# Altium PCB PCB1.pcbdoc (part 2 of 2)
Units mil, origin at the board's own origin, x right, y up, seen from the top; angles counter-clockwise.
Board outline 4437 x 2665.4 mil, 2 copper layers (Top Layer, Bottom Layer), stack 62.206 mil thick; 104 components, 76 nets, 470 pads, 389 vias.

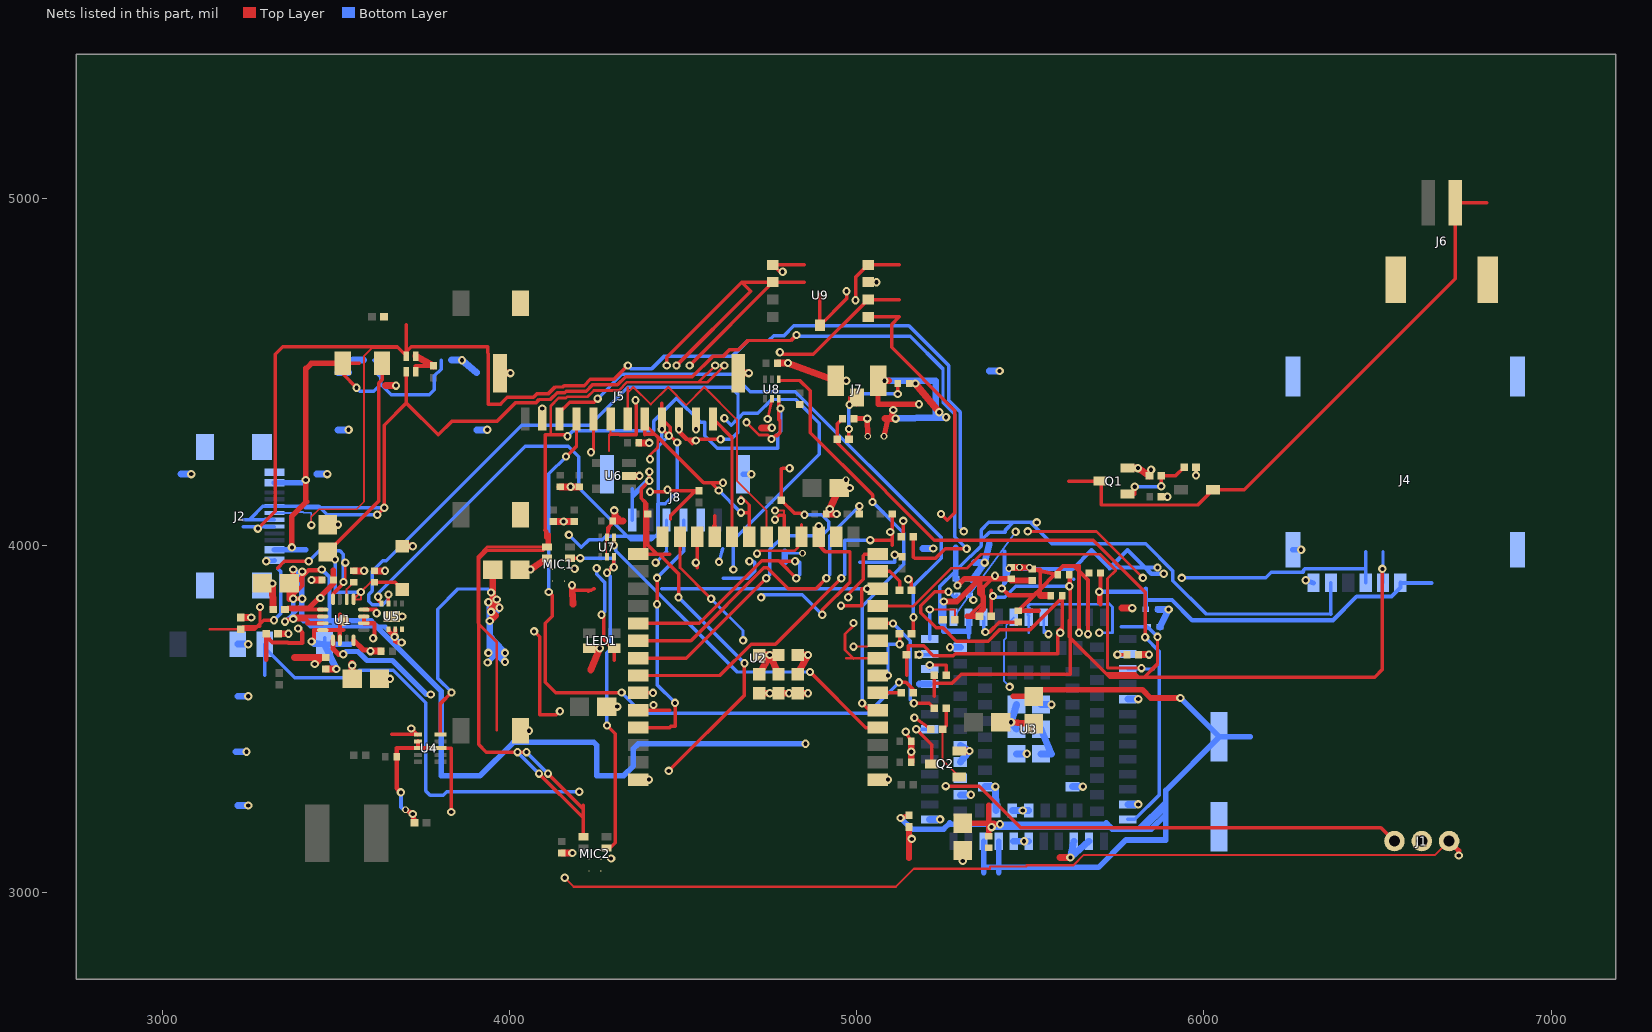
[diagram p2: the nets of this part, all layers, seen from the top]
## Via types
v1: diameter 24, hole 12, Top Layer to Bottom Layer, 378 vias
v2: diameter 19.8, hole 11.8, Top Layer to Bottom Layer, 8 vias
v3: diameter 19.7, hole 11.8, Top Layer to Bottom Layer, 3 vias

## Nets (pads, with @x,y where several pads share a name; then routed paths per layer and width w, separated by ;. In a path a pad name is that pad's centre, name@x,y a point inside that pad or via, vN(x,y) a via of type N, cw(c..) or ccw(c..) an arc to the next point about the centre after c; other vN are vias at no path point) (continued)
GND: C1.2 C2.2 C3.2 C4.2 C5.2 C6.2 C7.2 C8.2 C9.2 C10.2 C11.2 C12.2 C13.2 C14.2 C15.2 C16.2 C17.2 C18.2 C19.2 C20.2 C21.2 C22.2 C23.2 C24.2 C25.2 C26.2 C27.2 C28.2 C29.2 C30.2 C31.2 C32.2 C33.2 C34.2 C35.2 C36.2 C37.2 C38.2 C39.2 D1.2 D2.2 D3.2 D4.2 D5.2 D6.2 D8.2 J1.2 J2.8 J2.9 J2.10 J2.11 J2.A1B12 J2.B1A12 J4.5 J4.8 J4.9 J4.10 J4.11 J5.2 J5.13 J5.14 J6.3 J6.4 J7.1 J7.3 J8.2 J8.7 J8.8 LED1.2 MIC1.2 MIC1.3 MIC2.3 Q1.2 Q2.2 R1.2 R2.2 R4.2 R7.2 R8.2 R20.2 R25.2 R27.2 SW1.2 SW2.2 SW3.2 SW4.2 SW5.2 U1.4 U1.6 U1.8 U1.17 U2.1 U2.40 U2.41 U3.1 U3.10 U3.27 U3.34 U3.36 U3.37 U3.40 U3.41 U3.45 U3.46 U3.47 U3.48 U3.70 U3.71 U3.72 U3.73 U3.88 U3.89 U3.90 U3.91 U3.92 U3.93 U3.94 U3.95 U3.100 U4.2 U4.3 U4.8 U5.4 U5.9 U6.2 U7.2 U7.5 U8.2 U9.4 | length 9704.9
  Top Layer w5: U7.2@4278,3966.6 U7.5@4278,4023.4
  Top Layer w8: U7.5@4279.99,4023.45 4280.22,4024.22 4282,4030.86 4289.01,4057.01 v1(4300.71,4100.67) ; v1(4742.73,4363.89) U8.2@4754.99,4421.56
  Top Layer w10: U4.8@3792.11,3415.5 3831.19,3415.5 v1(3831.19,3231.61) ; v1(4179.06,3884.58) 4179.06,3870.89 4179.67,3870.89 4234.33,3870.89 ; 4226.19,3867.09 4234.33,3870.89 ; 4242.5,3874.7 4234.33,3870.89 ; U7.5@4280,4024 4280.22,4024.22 4282,4026 4282,4030.86 4282,4050 4289.01,4057.01 C29.2@4298,4066 ; C29.2@4296.54,4070 4306.03,4075.5 4315.55,4081 ; 4316,4066 4326.5,4070 ; C12.2@4911.54,4090 v1(4921.82,4104.74) ; v1(5140.5,3462.71) C10.2@5156.54,3435 ; C39.2@5150.54,4466 v1(5168.5,4466) ; v1(5165.49,3503.27) R27.2@5212.96,3470 ; C17.2@5505,3931.54 5528.5,3931.5 5528.5,3926.22 5528.5,3874.5 5528.5,3855 ; R25.2@5842.96,4200 v1(5847.66,4217.39) ; C31.2@5876.54,4140 v1(5894.5,4140)
  Top Layer w12: v1(3428.83,3722.9) 3436,3732 3436,3756 3510,3756 3510,3755.5 ; U1.4@3460.95,3755.47 3510,3755.5 ; U1.6@3510,3726 3510,3755.5 ; U1.6@3510.16,3725.95 3510.2,3755.5 ; 3510.2,3800.9 3510.2,3755.5 ; 3520,3755.5 3510.2,3755.5 ; 3674,3300 v1(3686,3288) ; 3674,3300.5 C18.2@3674.04,3390.5 3674,3415.5 U4.3@3735.02,3415.5 ; D2.2@3728.78,4500 3728.8,4517 R7.2@3780,4517.04 ; U4.2@3735.02,3435.18 U4.3@3735.02,3415.5 ; U4.8@3792.11,3415.5 U4.3@3735.02,3415.5 ; v1@5418,3876 5438,3856 5510,3856 ; C16.2@5445,3936.54 C17.2@5505,3931.54 5528.5,3926.22 C14.2@5570.74,3916.74 ; C37.2@5465,3811.54 5525,3811.5 ; C37.2@5466,3812 5510,3856 ; C14.2@5578.46,3915 C14.2@5570.74,3916.74 ; v1(5640,3748) 5640,3926 ; v1(5666,3744) 5666,3900 5640,3926 ; 3510,3755.5 3510.2,3755.5 ; 5510,3856 5528.5,3874.5 C14.2@5570.74,3916.74 ; C14.2@5570.74,3916.74 5594,3940 5626,3940 ; 5626,3940 5640,3940 5640,3926 ; 5626,3940 5640,3926
  Top Layer w15: U1.8@3550,3726 3578,3698 3588,3698 v1(3598.5,3695) ; v2(3699.3,3237.93) v1(3720.09,3225.93) R20.2@3725.46,3200.5 ; SW1.2@4030.9,3465.35 v1(4054.9,3465.4) ; C12.2@4911.54,4090 4928.74,4119.86 4954.8,4165 v2(4968.5,4188.73) ; C12.2@4912,4090 4918,4096 v1(4921.82,4104.74) ; C38.2@4991.54,4365 v1(5029.5,4365) v2(5031.28,4314.03) ; U9.4@5032.38,4758.03 v1(5056.4,4758) ; J7.3@5061.02,4474.1 5061,4406.1 v1(5178.78,4406.1) ; v2(5078.19,4314.14) 5089,4365 ; 5096.5,4365 v1(5104.53,4389.73) ; v2(5468.36,3936.65) 5469.42,3936.5 C17.2@5505,3931.54 ; v2@5475,3936.5 v2(5497,3936.5)
  Top Layer w20: R2.2@3225,3792.04 v1(3255,3792) ; C1.2@3285.63,3890 v1(3315.6,3890) R4.2@3317.96,3815 ; R1.2@3332.04,3745 v1(3362,3745) ; v1(3428.5,3900) C7.2@3458.46,3900 ; C5.2@3470,3643.46 v1(3500,3643.5) ; C3.2@3475,4059.37 v1(3505,4059.4) ; C6.2@3550,3926.54 v1(3580,3926.5) ; v1(3598.5,3695) C21.2@3628.46,3695 ; C2.2@3610,3926.54 v1(3640,3926.5) ; C4.2@3624.37,3615 v1(3654.4,3615) ; 3642,4460 v1(3672,4460) ; U5.9@3660,3795 v1(3690,3795) ; D8.2@3690,3997.4 v1(3720,3997.4) ; D1.2@3728.78,4545 R7.2@3780,4517.04 ; J5.14@3971.5,4495.95 v1(4001.5,4496) ; C19.2@4029.37,3930 v1(4059.4,3930) MIC1.2@4107.01,3962.89 ; J5.2@4093.5,4364.1 v1(4093.5,4394.1) ; C23.2@4125,4068.46 v1(4155,4068.5) C25.2@4185,4068.46 ; C22.2@4145,4168.46 v1(4175,4168.5) C28.2@4200,4168.46 ; C26.2@4150,3113.46 v1(4180,3113.5) ; v1(4179.06,3884.58) 4179.67,3870.89 4181.5,3830 ; LED1.2@4228.98,3703.34 v1(4259,3703.3) 4233,3640 ; C20.2@4279.37,3535 v1(4309.4,3535) ; C29.2@4296.54,4070 4326.5,4070 ; v1(4300.71,4100.67) C29.2@4306.03,4075.5 ; U6.2@4343.31,4199.99 v1(4373.3,4200) ; U2.40@4370.51,3324.8 v1(4400.5,3324.8) ; C27.2@4371.54,4295 v1(4401.5,4295) ; J5.13@4658.51,4495.94 v1(4688.5,4495.9) ; U2.41@4718.94,3573.62 v1(4748.9,3573.6) ; U2.41@4718.94,3628.74 v1(4748.9,3683.9) ; U2.41@4718.94,3683.86 v1(4748.9,3683.9) ; 4725,4338.5 v1(4755,4338.5) ; C30.2@4771.54,4525 v1(4801.5,4525) J7.1@4938.98,4474.1 v1(4969,4474.1) ; U2.41@4774.06,3573.62 v1(4804.1,3573.6) ; U2.41@4774.06,3628.74 v1(4748.9,3683.9) ; U2.41@4774.06,3683.86 v1(4748.9,3683.9) ; U2.41@4829.18,3573.62 v1(4859.2,3573.6) ; U2.41@4829.18,3628.74 v1(4859.2,3683.9) U2.41@4829.18,3683.86 ; C12.2@4911.54,4090 4912,4090 v1(4941.5,4090) ; v1(4921.82,4104.74) 4928.74,4119.86 C11.2@4949.37,4165 4954.8,4165 v1(4979.4,4165) ; U2.1@5059.49,3324.8 v1(5089.5,3324.8) ; J7.3@5061.02,4474.1 5091,4474.1 ; 5081.5,4365 5089,4365 5096.5,4365 v1(5111.5,4365) ; C9.2@5156.54,3375 v1(5156.5,3405) C10.2@5156.54,3435 ; v1(5168.5,4466) v1(5237.42,4383.44) ; Q2.2@5294.37,3407.4 v1(5324.4,3407.4) ; v1(5305,3090.6) C33.2@5305,3120.63 ; C8.2@5414.37,3490 v1(5444.4,3490) C34.2@5510,3485.63 ; C16.2@5445,3936.54 5469.42,3936.5 v2@5475,3936.5 ; 5528.5,3855 C15.2@5558.46,3855 ; 5585,3100.3 v1(5615,3100.3) ; 5763.1,3818.8 v1(5793.1,3818.8) ; Q1.2@5779.37,4222.4 v1(5809.4,4222.4) R25.2@5842.96,4200 ; C36.2@5811.54,3685 v1(5841.5,3685)
  Inner2 w12: v1(5640,3748) 5666,3722 5688,3722 ; v1(5666,3744) 5688,3722 ; v1(5866,3936) 5866,3880 ; v1(5884,3918) 5884,3898 5866,3880 ; 5688,3722 5708,3722 ; 5688,3722 5698,3712 5708,3722 ; 5708,3722 5866,3880
  Bottom Layer w5: U3.95@5278.46,3792.84 5324.22,3855.73 v1(5457.19,4038.74)
  Bottom Layer w6: 4792,3977.11 v2(4842.86,3977.11)
  Bottom Layer w10: SW4.2@3466.02,3715 SW4.2@3466,3733 ; v1(4602.55,3952.06) 4612.9,3990.7 ; 5227.1,4368.7 v1(5237.42,4383.44) ; D5.2@5324,3856 5324.22,3855.73 v1(5335.57,3842.21) ; v1(5417.39,3875.39) 5425,3891.7
  Bottom Layer w12: v1(3686,3288) 3686,3246 3692,3240 v2(3699.3,3237.93) ; 5425,3891.7 5425,3981.7 ; v2@5430,3932 5438.09,3932 5622,3932 5676,3986 5726,3936 ; v1(5866,3936) 5830,3936 ; v1(5884,3918) 5848,3918 5830,3936 ; 5726,3936 5730,3936 ; 5726,3936 5728,3934 5730,3936 ; 5730,3936 5780,3986 5830,3936 ; 5730,3936 5830,3936
  Bottom Layer w15: v1(3297.93,3953.99) J2.A1B12@3321.79,3956.49 ; SW4.2@3466,3714 3436,3714 v1(3428.83,3722.9) SW4.2@3466.02,3715 3541,3715 ; J8.8@4671.79,4204.64 v1(4695.8,4204.6) ; 5425,3891.7 5438.09,3932 v2(5438.29,3932.59) ; J4.8@6255.9,3987.12 v1(6279.9,3987.1) ; v1(6292.98,3899.12) J4.5@6315.8,3891.7
  Bottom Layer w20: 3051.9,4205 v1(3081.9,4205) ; 3211,3405 v1(3241,3405) ; 3216,3250 v1(3246,3250) ; 3216,3565 v1(3246,3565) ; SW5.2@3216.02,3715 v1(3246,3715) ; 3443.6,4205 v1(3473.6,4205) ; SW4.2@3466.02,3715 v1(3500,3643.5) ; 3505.4,4332.7 v1(3535.4,4332.7) ; 3505.4,4497.3 3535.4,4497.3 ; 3548,4533.3 3578,4533.3 ; 3832,4533.3 v1(3862,4533.3) 3904.6,4497.3 ; 3904.6,4332.7 v1(3934.6,4332.7) ; 4792,3951.3 4792,3977.11 4792,3981.3 ; v1(5079,4474.1) 5227.1,4474.1 5227.1,4368.7 ; v1(5111.5,4365) 5227.1,4368.7 ; 5179.6,3599.9 U3.10@5209.57,3599.91 ; 5189.7,3990.7 v1(5219.7,3990.7) ; U3.1@5209.57,3210.16 v1(5239.6,3210.2) ; v1(5257.1,4368.7) 5227.1,4368.7 ; v1(5268.2,3706.2) U3.100@5298.15,3706.22 ; U3.45@5298.15,3281.01 v1(5328.2,3281) ; U3.47@5298.15,3375.51 v1(5324.4,3407.4) U3.48@5298.15,3422.76 ; 5333,3900 v1(5368,3950) ; 5338,3950 v1(5368,3950) ; U3.73@5369.02,3304.64 v1(5399,3304.6) U3.72@5400.51,3235.74 ; 5381.2,4003.1 v1(5368,3950) ; 5381.2,4502.3 v1(5411.2,4502.3) ; U3.71@5447.76,3235.74 v1(5477.8,3235.7) U3.70@5495,3235.74 ; U3.41@5451.69,3147.16 v1(5481.7,3147.2) U3.40@5495,3147.16 ; U3.89@5459.57,3399.12 v1(5489.6,3399.1) ; U3.90@5459.57,3469.99 v1(5444.4,3490) U3.91@5459.57,3540.86 ; U3.94@5530.43,3399.12 5560.4,3399.1 U3.93@5530.43,3469.99 ; U3.92@5530.43,3540.86 v1(5560.4,3540.9) ; U3.88@5620.98,3304.64 v1(5651,3304.6) ; U3.37@5624.92,3147.16 v1(5615,3100.3) U3.36@5668.23,3147.16 ; U3.34@5780.43,3253.45 v1(5810.4,3253.5) ; U3.27@5780.43,3556.61 v1(5810.4,3556.6) ; D3.2@5868,3815 v1(5898,3815) D4.2@5873,3765
  other v1: 4291.7,3097.5 4186.7,3932.5
GPIO0_BOOT: J8.6 R6.1 SW4.1 U2.27 | length 3268.4
  Top Layer w10: U2.27@4370.51,3974.8 4423.2,3974.8 ; U2.27@4388,3978 4388,4126 ; R6.1@4394,4094 4394,4120 4388,4126 ; 4397,4000 R6.1@4397.04,4090 ; 4398,4000 4423.2,3974.8 ; v1(4402,4212) v1(4402,4186) 4378,4162 4378,4136 4388,4126 ; 4424,3974 4423.2,3974.8 ; 4430,3974 4486,3918 v1(4486,3850) ; v1(4458,3350) 4676,3568 v1(4676,3660) ; 4460.5,3974.8 4423.2,3974.8
  Top Layer w15: U2.27@4370.51,3974.8 U2.27@4388,3978
  Inner2 w10: v1(4200,3290) 4260,3350 v1(4458,3350)
  Bottom Layer w10: 3294,3625 SW4.1@3293.98,3715 ; SW4.1@3298,3700 3380,3618 3544,3618 3566,3640 3664,3640 3758,3546 3758,3292 3770,3280 3808,3280 3818,3290 v1(4200,3290) ; J8.6@4352,4072 4352,4136 ; 4352,4162.8 4352,4144 ; J8.6@4352.9,4072 J8.6@4352.89,4072.75 4352.9,4136.9 ; v1(4402,4186) 4352.9,4136.9 ; v1(4402,4212) 4402,4194 4352,4144 ; v1(4486,3850) v1(4676,3660) ; 4352,4136 4352.9,4136.9 ; 4352,4136 4352,4144
I2C_SCL: J5.10 U2.17 U5.7 | length 3579
  Top Layer w9.92: U5.7@3650.16,3831.91 v1(3650.16,3858.19) ; J5.10@4487.24,4364.05 4487.24,4325.63 4507.24,4305.63 4512.37,4305.63 v1(4607.24,4305.63)
  Top Layer w10: v1@4487.2,4329.1 J5.10@4487.2,4364.1 ; v1@4488,4330 4512.37,4305.63 4526,4292 v1(4536,4302) ; U2.17@4888,4022 4888,4002 4908,3982 4980,3982 4980,3894 4900,3814 v1(4900,3800) ; U2.17@4890,4025.2 v1@4890,4060.2
  Inner1 w10: v1(4536,4302) 4554,4302 v1(4618,4366)
  Inner2 w10: v1(4644,3930) v1(4724,3850)
  Bottom Layer w9.92: v1(3650.16,3858.19) 3650.16,3844.47 3633.88,3828.19 3603.88,3828.19 3593.88,3838.19 3593.88,3858.19 3603.88,3868.19 3603.88,3925.63 3633.88,3955.63 3643.88,3955.63 4033.88,4345.63 4229.76,4345.63 4339.76,4455.63 4637.24,4455.63 4657.24,4435.63 4657.24,4365.24 4657.24,4325.63 4637.24,4305.63 v1(4607.24,4305.63)
  Bottom Layer w10: v1(4618,4366) 4638,4346 4657.24,4365.24 4672,4380 4714,4380 4754,4420 4824,4420 4892,4352 4892,4262 4644,4014 v1(4644,3930) ; v1(4724,3850) 4732,3858 4842,3858 v1(4900,3800)
  other v1: 4890,4055.2 4487.2,4334.1
I2C_SDA: J5.9 U2.12 U5.8 | length 3950.8
  Top Layer w9.92: v1(3620.47,3851.91) 3620.47,3841.91 U5.8@3630.47,3831.91 ; J5.9@4438.03,4335.63 v1(4458.03,4315.63)
  Top Layer w10: v1(4438,4334.1) J5.9@4438.03,4364.05 ; 4438,4409.1 J5.9@4438.03,4364.05 ; v1(4482,4296) 4462,4316 4462,4340 J5.9@4438.03,4364.05 ; v1(4954,3826) 5014,3826 5014,3870 ; 5014.5,3874.8 v1(5029.5,3874.8) U2.12@5059.49,3874.8
  Inner2 w10: v1(4170,4030) 4194,4054 4214,4054 4234,4034 4234,4016 4280,4016 4290,4026 4316,4026 4350,3992 4620,3992 4668,3944 4668,3942 4718,3892 4718,3890 4782,3826 v1(4954,3826)
  Bottom Layer w9.92: v1(3620.47,3851.91) 3620.47,3861.91 4044.19,4285.63 4168.03,4285.63 4198.03,4255.63 4198.03,4165.63 4337.66,4026 4348.03,4015.63 4408.03,4015.63 4418.4,4026 4426,4033.6 4428.03,4035.63 4428.03,4120 4428.03,4285.63 4438,4295.6 v1(4458.03,4315.63)
  Bottom Layer w10: v1(4170,4030) 4206,3994 4228,4016 4266,4016 4276,4026 4337.66,4026 4418.4,4026 4426,4026 4426,4033.6 4426,4120 4428.03,4120 4448,4120 4482,4154 v1(4482,4296) ; 4438,3874.8 v1(5029.5,3874.8) ; 4438,4295.6 v1(4438,4334.1)
LCD_BL_PWM: J5.8 U2.21 | length 1098.7
  Top Layer w8: J5.8@4392,4346 4418,4320 ; v1(4404,4248) 4404,4260 4426,4282 4426,4312 ; 4666,4140 4690,4116
  Top Layer w10: 4388,4320 4388.8,4320 ; 4388.8,4319.1 4388.8,4320 ; J5.8@4388.8,4364.1 4388.8,4320 ; v1(4602,4158) 4580,4180 ; v1(4614,4180) 4580,4180 ; v1(4666,4094) 4686,4094 ; v1(4666,4128) v1@4670,4132 ; U2.21@4690,4025.2 4690,4115.2 ; 4388.8,4320 4418,4320 4426,4312 4558,4180 4580,4180
  Inner2 w8: v1(4404,4248) 4414,4258 4548,4258 4666,4140
  Inner2 w10: v1(4614,4180) v1(4666,4128)
  Bottom Layer w10: v1(4602,4158) v1(4666,4094)
LCD_CS: J5.5 U2.18 | length 993.8
  Top Layer w8: v1(4234,4268) 4240,4274 v1@4242,4274 ; v1@4241.2,4274.1 J5.5@4241.2,4364.1 ; v1(4712,3976) 4720,3984 4820,3984 4842,4006 U2.18@4842,4022 ; U2.18@4840,4025.2 4840,4060.2
  Inner2 w8: v1(4234,4268) 4244,4258 4244,4118 4336,4026 4370,4026 4372,4024 4380,4032 4412,4032 4420,4040 4420,4044 4644,4044 v1(4712,3976)
LCD_DC: J5.6 U2.19 | length 1768.3
  Top Layer w6: 4286,4272 4286,4316 4288,4318 ; 4290.4,4319.1 4290.4,4320 J5.6@4290.4,4364.1 ; v1(4764,4100) 4790,4100 ; 4790,4086 4790,4100 ; 4790,4100.2 4790,4100
  Top Layer w10: 4288,4318 4290,4320 4290.4,4320 4314,4320 4316,4318 4364,4318 4364,4416 v1(4362,4418) ; v1(4764,4074) 4776,4086 4790,4086 ; U2.19@4790,4025.2 4790,4085.2
  Inner2 w6: 4286,4272 4566,4272 4592,4272 v1(4764,4100)
  Inner2 w10: v1(4362,4418) 4362,4474 4432,4544 4526,4544 4562,4508 4562,4276 4566,4272 v1(4764,4074)
LCD_MOSI: J5.4 R22.2 | length 1956.3
  Top Layer w10: v1(4111.96,3865.59) 4121.96,3855.59 4121.96,3795.59 4101.96,3775.59 4101.96,3605.59 4131.96,3575.59 v1(4321.96,3575.59) ; v1(4161.96,4255.59) 4191.96,4285.59 J5.4@4191.96,4364.05 ; v1(5121.37,3605) 5141.37,3605 5162.04,3584.33 R22.2@5162.04,3575
  Bottom Layer w10: v1(4111.96,3865.59) 4111.96,4205.59 v1(4161.96,4255.59) ; v1(4321.96,3575.59) 4381.96,3515.59 5031.96,3515.59 v1(5121.37,3605)
LCD_MOSI_MCU: R22.1 U2.6 | length 68.6
  Top Layer w10: U2.6@5059.49,3574.8 5059.7,3575 R22.1@5127.96,3575
LCD_RST: J5.7 U2.20 | length 903.9
  Top Layer w6: J5.7@4339.6,4364.1 4339.6,4454.1 ; 4342,4442 4356,4456 4406,4406 4456,4456 4508,4404 4560,4456 4654,4362 4654,4186 4740,4100 ; U2.20@4740,4025.2 4740,4100 ; 4740,4100.2 4740,4100
LCD_SCLK: J5.3 R23.2 | length 1671.7
  Top Layer w10: J5.3@4142.75,4364.05 4142.75,4382.52 4172.75,4412.52 4242.75,4412.52 v1(4252.75,4422.52) ; R23.2@5157.04,3745 5162.75,3750.71 v1(5162.75,3792.52)
  Bottom Layer w10: v1(4252.75,4422.52) 4322.75,4492.52 4642.75,4492.52 4692.75,4442.52 4822.75,4442.52 5242.75,4022.52 5242.75,3962.52 5162.75,3882.52 v1(5162.75,3792.52)
LCD_SCLK_MCU: R23.1 U2.7 | length 183.7
  Top Layer w10: U2.7@5059.49,3624.8 v1(5089.5,3624.8) ; v1(5123,3715) R23.1@5122.96,3745
  Bottom Layer w10: v1(5089.5,3624.8) 5089.5,3715 v1(5123,3715)
LED_DATA: LED1.3 U2.24 | length 703.7
  Top Layer w10: v1(4264,3800) 4270,3794 4270,3728 4294,3704 LED1.3@4302,3704 ; 4301,3668.3 LED1.3@4301.02,3703.34 ; 4540,3935.2 U2.24@4540,4025.2
  Inner2 w10: v1(4250,3934) 4292,3976 4510,3976 v1(4536,3950)
  Bottom Layer w10: v1(4250,3934) 4250,3916 4274,3892 4274,3810 v1(4264,3800)
LTE_ANT: C38.1 R29.1 U3.35 | length 1862.4
  Top Layer w10: R29.1@4942.96,4305 4942.96,4295 5222.96,4015 5680.43,4015 5830.43,3865 v1(5830.43,3735) ; R29.1@4942.96,4305 4943,4349.5 C38.1@4958.46,4365
  Bottom Layer w10: U3.35@5780.43,3210.16 5800.43,3210.15 5870.43,3280.15 5870.43,3695 v1(5830.43,3735)
LTE_ANT_CONN: C39.1 J7.2 R29.2 | length 346.8
  Top Layer w10: R29.2@4977.04,4305 v1(4977,4335) ; v1(4978.79,4404.69) 4978.79,4425.9 J7.2@5000,4425.9 J7.2@5000,4404.69 ; v1(5117.5,4436) C39.1@5117.46,4466
  Bottom Layer w10: v1(4977,4335) 4977,4404.69 v1(4978.79,4404.69) 5010.09,4436 v1(5117.5,4436)
MIC_CLK_1V8: MIC1.4 MIC2.4 U7.3 | length 1064.8
  Top Layer w6: v1(4299.7,3936.6) U7.3@4299.69,3966.55
  Top Layer w9.92: MIC2.4@4277.99,3127.89 4288.64,3127.89 4303.32,3142.57 4303.32,3457.24 v1(4279.69,3480.87) ; v1(4279.69,3920.87) 4299.69,3940.87 U7.3@4299.69,3966.55
  Top Layer w10: MIC1.4@4172.99,3962.89 v1(4203,3962.9)
  Bottom Layer w9.92: v1(4279.69,3480.87) 4279.69,3690.87 4289.69,3700.87 4289.69,3910.87 v1(4279.69,3920.87)
  Bottom Layer w10: v1(4203,3962.9) 4299.7,3962.9 v1(4299.7,3936.6)
MIC_DATA_1V8: MIC1.1 MIC2.1 U8.3 | length 4968.9
  Top Layer w8: 3962,3468 3962,3722 3910,3774 3908,3776 3908,3968 3936,3996 4106,3996 4107,3996 4114,3996 4114,4032 4112,4032 4107,4037 4105,4039 ; 4102,4044 4102,4042 4102,4022 4106,4018 ; 4118,4318 4118,4402 4140,4424 4162,4424 4166,4428 4224,4428 4242,4446 4314,4446 4338,4470 4544,4470 ; v1(4592,4518) 4544,4470 ; v1(4618,4518) 4570,4470 4544,4470 ; v1(4682,4354) 4718,4318 4744,4318 4748,4314 v1@4762,4314 ; v1(4754,4306) v1@4762,4314 ; 4778,4360 4778,4326 ; v1@4762,4314 4766,4318 4770,4318 4778,4326 ; v1@4762,4314 4770,4314 4778,4322 4778,4326
  Top Layer w10: v1(4048,3404) 3932,3404 3910,3426 3910,3774 3910,3962 3934,3986 4096,3986 MIC1.1@4106,3996 ; v1(4084,3342) 4208,3218 ; 4101,4043 4102,4042 4105,4039 ; 4102,4044 4102,4318 4118,4318 4162,4318 v1(4166,4314) ; MIC1.1@4107.01,3995.26 4107,3996 4107,4037 4107,4040.3 ; v1(4110,3342) 4212,3240 ; MIC2.1@4212.01,3160.26 4212,3240 ; 4212,3250.3 4212,3240 ; 4774.7,4361.6 U8.3@4774.69,4421.56 ; v1@4778,4394 v1(4780,4394)
  Inner2 w8: v1(4592,4518) 4682,4428 v1(4682,4354) ; v1(4618,4518) 4704,4432 4704,4356 v1(4754,4306)
  Bottom Layer w10: v1(4022,3404) v1(4084,3342) ; v1(4048,3404) v1(4110,3342) ; v1(4166,4314) 4182,4330 4414,4330 4414,4358 4480,4424 4550,4354 4562,4354 4562,4316 4598,4280 4772,4280 4772,4320 4780,4328 v1(4780,4394)
MIC_PDM_CLK: U2.4 U7.4 | length 1006.6
  Top Layer w9.92: v1(4299.69,4000.12) U7.4@4299.69,4023.45 ; v1(4865,3634.8) 5025,3474.8 U2.4@5059.49,3474.8
  Bottom Layer w9.92: v1(4299.69,4000.12) 4305.01,3994.8 4305.01,3984.8 4655,3634.8 v1(4865,3634.8)
MIC_PDM_DATA: U2.5 U8.4 | length 1218.6
  Top Layer w9.92: U8.4@4774.69,4478.44 4778.33,4474.8 4835,4474.8 4865,4444.8 4865,4324.8 5045,4144.8 v1(5045,4124.8) ; v1(5015,3544.8) 5035,3524.8 U2.5@5059.49,3524.8
  Bottom Layer w9.92: v1(5015,3544.8) 5015,3824.8 5135,3944.8 5135,4034.8 v1(5045,4124.8)
MICROSD_N5: R12.1 U9.7 | length 3545.6
  Top Layer w10: v1(4404,4154) v1@4452,4154 ; v1(4452,4518) 4452,4542 4668,4758 ; v1@4455,4157 R12.1@4545,4157.04 ; 4462.8,4074.84 4462.8,4084.84 4532.8,4154.84 4542.8,4154.84 R12.1@4545,4157.04 ; v1(4480,4518) 4694,4732 4668,4758 ; v1(4518,4518) U9.7@4758,4758 ; R12.1@4545,4157.04 R12.1@4545,4157.04 ; 4667.6,4758 4668,4758 ; 4847.6,4758 U9.7@4758,4758 ; 4668,4758 U9.7@4757.6,4758.03 U9.7@4758,4758
  Inner2 w10: v1(4404,4154) 4298,4154 4292,4160 ; v1(4452,4518) 4452,4474 ; v1(4454,4160) 4292,4160 ; v1(4480,4518) 4480,4502 4452,4474 ; v1(4518,4518) 4320,4320 4298,4320 ; v1(4690,3954) 4714,3930 4738,3954 4738,3984 4704,4018 4704,4060 4550,4060 4550,4126 4296,4126 4294,4124 4272,4124 4272,4160 ; 4272,4160 4260,4160 4260,4282 4272,4294 ; 4272,4160 4292,4160 ; 4272,4160 4272,4294 ; 4272,4294 4298,4320 ; 4298,4320 4452,4474
  Bottom Layer w10: 4615.43,3904.84 4685.43,3904.84 4705.43,3924.84 4705.43,3951.34 ; v1(4690,3954) 4702,3954
MICROSD_N6: R13.1 U9.1 | length 1452.3
  Top Layer w10: U9.1@4893.15,4633.62 4893.2,4723.6 ; U9.1@4894,4634 4970,4710 v1(4970,4732) ; v1(5108.79,3972.51) 5130,3972.51 R13.1@5130,3967.04
  Inner2 w10: v1(4970,4732) 5066,4732 5142,4656 5142,4224 5268,4098 5268,4004 5230,3966 5118,3966 v1(5108.79,3972.51)
  Bottom Layer w10: 5008.6,3951.3 5108.79,3951.3 v1(5108.79,3972.51)
MODEM_DTR: U2.25 U3.19 | length 1368.4
  Top Layer w8: 4490,3935.2 4490,3936 ; U2.25@4490,4025.2 4490,3936 ; v1(4580,3846) 4490,3936
  Inner2 w8: v1(4672,3726) 4682,3736 5068,3736 5112,3692 5154,3692 5198,3736 5344,3736 5356,3724 5532,3724 v1(5552,3744)
  Bottom Layer w8: v1(4580,3846) 4672,3754 v1(4672,3726) ; 5538.3,3747.8 U3.19@5538.31,3792.84 ; 5542,3754 v1(5552,3744)
MODEM_PWRKEY_DRV: R26.1 U2.10 | length 364.5
  Top Layer w10: U2.10@5059.49,3774.8 v1(5104.02,3774.81) ; v1(5164.02,3544.81) 5208.15,3544.81 R26.1@5222.96,3530
  Bottom Layer w10: v1(5104.02,3774.81) 5154.02,3724.81 5154.02,3554.81 v1(5164.02,3544.81)
MODEM_PWRKEY_N: Q2.3 U3.7 | length 157.1
  Top Layer w10: v1(5170.94,3470) 5215.63,3425.31 Q2.3@5215.63,3370
  Bottom Layer w10: v1(5170.94,3470) U3.7@5209.57,3469.99
MODEM_RESET_N: C37.1 U3.15 | length 151.6
  Top Layer w10: v1(5370,3750) 5382,3750 5410,3778 ; 5410,3778.5 C37.1@5465,3778.46
  Bottom Layer w10: v1@5365.1,3747.8 U3.15@5365.08,3792.84
MODEM_RXD: U2.8 U3.18 | length 1897.7
  Top Layer w8: 4969.5,3674.8 4989.2,3674.8 ; 4990,3674 4989.2,3674.8 ; v1(4990,3776) 4990,3768 4966,3744 4966,3698 4989.2,3674.8 ; U2.8@5060,3674.8 U2.8@5059.49,3674.8 4989.2,3674.8 ; v1(5492,4040) 5690,4040 v1(5824,3906)
  Inner2 w8: v1(4990,3776) 5072,3776 5094,3798 5124,3798 5156,3766 5218,3766 v1(5492,4040) ; v1(5698,3748) 5698,3780 v1(5824,3906)
  Bottom Layer w8: 5495,3747.8 U3.18@5495,3792.84 ; U3.18@5496,3796 5492,3800 5498,3806 5492,3812 5498,3818 5492,3824 5498,3830 5720,3830 5724,3834 5736,3822 5736,3748 v1(5698,3748)
MODEM_STATUS: U2.11 U3.25 | length 1232.1
  Top Layer w8: U2.11@5059.49,3824.8 5149.5,3824.8 ; 5150,3824 5162,3824 5272,3934 5318,3934 5358,3974 5700,3974 5746,3928 5722,3904 5722,3646 v1(5820,3646)
  Bottom Layer w8: U3.25@5780.43,3643.22 5855.4,3643.2
MODEM_TXD: U2.9 U3.17 | length 790.2
  Top Layer w5: v1(4990,3708) 5030,3708 U2.9@5059.49,3724.8
  Inner2 w5: v1(4990,3708) 5038,3708 5114,3632 5400,3632 v1(5440,3592)
  Bottom Layer w5: v1(5440,3592) 5424,3608 5424,3728 5430,3734 5430,3770 U3.17@5452,3792
MODEM_VDD_EXT: C36.1 U3.24 | length 59.6
  Top Layer w9.84: v1(5750.4,3685) C36.1@5778.46,3685
  Bottom Layer w9.84: v1(5750.4,3685) 5780.4,3685 U3.24@5780.43,3686.53
MOTOR_GATE: Q1.1 R24.2 R25.1 | length 226.4
  Top Layer w10: Q1.1@5779.37,4147.6 5800.61,4147.6 v1(5800.61,4168.81) ; v1(5877,4170) R25.1@5877.04,4200 5918,4200 R24.2@5942.96,4225
  Bottom Layer w10: v1(5800.61,4168.81) 5877,4168.81 v1(5877,4170)
MOTOR_N: D7.2 J6.2 Q1.3 | length 1750.1
  Top Layer w10: 5610.6,4185 Q1.3@5700.63,4185 ; Q1.3@5704,4182 5704,4116 5982,4116 D7.2@6026,4160 ; D7.2@6026.16,4160 6116,4160 ; 6116.2,4160 6116,4160 ; J6.2@6724,4982 6724,4768 6116,4160 ; J6.2@6724.41,4986.95 6814.4,4986.9
MOTOR_PWM: R24.1 U2.35 | length 1960.6
  Top Layer w10: U2.35@4370.51,3574.8 v1(4412.59,3574.8) ; v1(5977.04,4201.37) R24.1@5977.04,4225
  Inner2 w10: v1(4412.59,3574.8) 4588.16,3750.37 5323.77,3750.37 5414.67,3841.27 5723.96,3841.27 5986.95,4104.26 5986.95,4191.46 v1(5977.04,4201.37)
POWER_CHARGE_N4: C7.1 J1.3 R4.1 U1.1 | length 4624.5
  Top Layer w6: v1(4158,3042) 4184,3016 5112,3016 5164,3068 5384,3068 5384,3074 5488,3074 5488,3078 5624,3078 5654,3108 6666,3108 J1.3@6706,3148
  Top Layer w10: 3492,3886 C7.1@3492,3890 ; v1(4070,3752) 4086,3736 4086,3512 4134,3512 v1(4144,3522) ; v1(6734,3106) 6734,3120
  Top Layer w12: 3370.9,3814.5 U1.1@3460.95,3814.53
  Top Layer w15: J1.3@6706.28,3147.69 6734,3120
  Top Layer w16: R4.1@3352.04,3815 3362,3818 3420,3818 3492,3890 C7.1@3492,3900 ; C7.1@3491.54,3900 3491.5,3928
  Inner2 w6: v1(4158,3042) 4158,3124
  Inner2 w10: v1(3454,3848) 3496,3848 3498,3850 3520,3850 3560,3890 4064,3890 4064,3758 v1(4070,3752) ; v1(4144,3522) 4152,3514 4152,3204 4118,3170 4160,3128 4180,3148 ; 6734,3072 v1(6734,3106)
POWER_CHARGE_N5: R1.1 U1.12 | length 518.5
  Top Layer w12: 3298,3670 R1.1@3298,3738 ; R1.1@3298,3746 R1.1@3297.96,3745 R1.1@3298,3738 ; v1(3390,3760) 3402,3748 3402,3718 3362,3718 3360,3720 3316,3720 R1.1@3298,3738 ; U1.12@3579.05,3814.53 v1@3614.1,3814.5 ; v1(3616,3804) v1@3616,3808
  Inner2 w12: v1(3390,3760) 3396,3766 3574,3766 3612,3804 v1(3616,3804)
POWER_CHARGE_N6: R2.1 U1.16 | length 1234.7
  Top Layer w8: 3135,3758 R2.1@3225,3757.96 ; R2.1@3224,3760 3230,3766 3272.42,3766 3280,3766 3280,3773.58 v1(3280,3822) ; 3490,3862 3520.48,3892.48 3526,3898 v1(3526,3950) ; U1.16@3490.48,3859.73 3490.48,3862
  Top Layer w10: R2.1@3225,3757.96 3264.38,3757.96 3272.42,3766 3280,3773.58 3290.48,3784.05 v1(3320.48,3784.05) ; 3330.48,3934.05 3350.48,3954.05 v1(3420.48,3954.05) ; U1.16@3490.47,3844.05 3490.48,3859.73 3520.48,3889.73 3520.48,3892.48 v1(3520.48,3894.05)
  Inner2 w8: v1(3280,3822) 3328,3870 3446,3870 v1(3526,3950)
  Bottom Layer w10: v1(3320.48,3784.05) 3340.48,3804.05 3340.48,3924.05 3330.48,3934.05 ; v1(3420.48,3954.05) 3450.48,3984.05 3510.48,3984.05 3520.48,3974.05 v1(3520.48,3894.05)
POWER_CHARGE_N7: C6.1 U1.14 | length 57.8
  Top Layer w6: U1.14@3529.84,3844.05 3529.8,3873.3 C6.1@3550,3893.46
PWRKEY_BASE: Q2.1 R26.2 R27.1 | length 221.2
  Top Layer w6: R27.1@5247.04,3470 5247,3380 Q2.1@5294.37,3332.6
  Top Layer w10: R27.1@5247.04,3470 5257,3480 R26.2@5257.04,3530
SD_CS: R11.1 U2.34 U9.2 | length 2028.9
  Top Layer w10: U2.34@4370.51,3624.8 4605.23,3624.8 4695.28,3714.84 4765.28,3714.84 v1(4955.28,3904.84) ; U9.2@5032.38,4658.03 5122,4658 ; v1(5038.36,4014.94) 5102,4014.94 ; v1(5096,4038) v1@5098,4038 ; 5102,4000 5102,4014.94 ; R11.1@5102.04,4090 5102,4014.94 ; 5122.4,4658 5122,4658 ; v1(5242,4090) 5260,4072 5282,4094 5282,4388 5100,4570 5100,4636 5122,4658
  Inner2 w10: v1(5096,4038) 5096,4068 5124,4096 5142,4096 5148,4090 v1(5242,4090)
  Bottom Layer w10: v1(4955.28,3904.84) 4965.28,3914.84 4965.3,4014.94 v1(5038.36,4014.94)
SD_MISO: R14.1 U2.33 U9.6 | length 1765.9
  Top Layer w10: U2.33@4370.51,3674.8 4508.69,3674.8 v1(4738.74,3904.84) ; U9.6@4757.6,4808.03 U9.6@4758,4808 ; 4782,4220 R14.1@4782.04,4130 4820,4092 4838,4092 v1(4848.74,4087.84) ; 4786,4222 v1(4806,4222) ; v1(4786,4788) 4778,4788 U9.6@4758,4808 ; 4847.6,4808 U9.6@4758,4808
  Inner2 w10: v1(4786,4788) 4786,4582 4826,4542 4826,4222 v1(4806,4222)
  Bottom Layer w10: v1(4738.74,3904.84) 4748.74,3914.84 4748.74,3987.84 4788.74,4027.84 4898.74,4027.84 4918.74,4047.84 4918.74,4067.84 4898.74,4087.84 v1(4848.74,4087.84)
SD_MOSI: R15.1 U2.32 U9.5 | length 1739.8
  Top Layer w10: U2.32@4370.51,3724.8 4521.92,3724.8 4731.97,3934.84 4741.97,3934.84 4801.96,3874.84 4881.96,3874.84 v1(4911.96,3904.84) ; v1(4996,4706) 4996,4772 U9.5@5032,4808 ; R15.1@5007.04,4090 v1(5007.04,4112.91) ; U9.5@5032.38,4808.03 5122.4,4808
  Inner2 w10: v1(4996,4706) 4996,4422 5004,4414 5004,4124 v1(5007.04,4112.91)
  Bottom Layer w10: v1(4911.96,3904.84) 4921.96,3914.84 4921.96,4027.84 v1(5007.04,4112.91)
SD_SCLK: U2.31 U9.3 | length 1744.5
  Top Layer w10: U2.31@4370.51,3774.8 4545.32,3774.81 4725.35,3954.84 4775.35,3954.84 v1(4825.35,3904.84) ; v1(4778,4556) 4784,4550 4874,4550 U9.3@5032,4708 ; 4780,3954 v1(4822,3954) ; U9.3@5032.38,4708.03 5122.4,4708
  Inner2 w10: v1(4778,4556) 4778,4530 4754,4506 4780,4480 4720,4420 4780,4360 4780,4118 4790,4108 4790,3986 v1(4822,3954)
  Bottom Layer w10: v1(4825.35,3904.84) 4835.35,3914.84 4835.35,3951.34
SIM_CLK: R16.1 U3.13 | length 187.6
  Top Layer w6: v1(5209.6,3815) 5282,3815 R16.1@5282.04,3785
  Bottom Layer w10: U3.13@5209.57,3729.84 v1(5209.6,3815)
SIM_DATA: R17.1 U3.11 | length 89.2
  Top Layer w10: v1(5209.6,3655) 5257,3655 R17.1@5257.04,3625
  Bottom Layer w6: U3.11@5209.57,3643.22 v1(5209.6,3655)
SIM_N2: C15.1 D5.1 J4.2 R19.2 | length 2546.9
  Top Layer w10: 5143,3625 R19.2@5142.96,3685 ; R19.2@5148,3684 5148,3710 5192,3710 5220,3682 5278,3682 5284,3688 5578,3688 5578,3752 5591.5,3765.5 ; v1(5264,3866) 5224,3866 5184,3826 5184,3806 5228,3762 5248,3762 5286,3724 5378,3724 5410,3756 5498,3756 C15.1@5591.5,3849.5 ; v1(5586,3748) 5592,3754 5592,3766 ; C15.1@5591.54,3855 C15.1@5591.5,3849.5 ; C15.1@5592,3854 C15.1@5592,3850 ; 5591.5,3765.5 5592,3766 ; 5591.5,3765.5 C15.1@5591.5,3849.5 ; C15.1@5591.5,3849.5 C15.1@5592,3850 ; 5592,3766 C15.1@5592,3850
  Inner2 w10: v1(5586,3748) 5640,3694 5724,3694 v1(5936,3906)
  Bottom Layer w10: v1(5264,3866) 5280,3850 D5.1@5288,3856 ; v1(5936,3906) 6178,3906 6194,3922 6286,3922 6286,3926 6288,3926 6288,3930 6290,3932 6462,3932 ; J4.2@6465.8,3891.7 6465.8,3981.7
SIM_N4: C13.1 D3.1 J4.3 R16.2 | length 1210.7
  Top Layer w12: v1(5698,3866) 5698,3834 5701.5,3830.5 ; 5701.5,3830 5701.5,3830.5 ; C13.1@5701.54,3920 5701.5,3830.5 ; 5702,3830 5701.5,3830.5
  Bottom Layer w12: v1(5698,3866) 5826,3866 ; D3.1@5832,3815 5832,3875 ; 5838,3842 5908,3842 5966,3784 6372,3784 6440,3852 6540,3852 6566,3878 J4.3@6566,3891.7 ; J4.3@6565.8,3891.7 J4.3@6566,3891.7 ; J4.3@6566,3892 J4.3@6566,3891.7 ; 6655.8,3891.7 J4.3@6566,3891.7
SIM_N6: C14.1 D4.1 J4.7 R17.2 R18.1 | length 2822.2
  Top Layer w10: 5223,3565 R17.2@5222.96,3625 ; 5228,3602 5274,3602 5300,3628 5614,3628 5614,3734 ; R18.1@5387.04,3795 5387,3870 ; v1@5611.5,3880 C14.1@5611.54,3915 ; v1@5612,3880 v1@5614,3878 ; C14.1@5612,3914 5614,3912 v1@5614,3878 ; v1(5866,3736) 5866,3658 5828,3620 ; v1(6514,3932) 6514,3642 6492,3620 5828,3620 ; 5614,3734 5612,3736 5612,3784 5614,3784 ; 5614,3734 5614,3784 ; 5614,3734 5718,3630 ; 5614,3784 v1@5614,3878 ; 5718,3630 5802,3630 5812,3620 ; 5718,3630 5728,3620 5812,3620 ; 5812,3620 5828,3620
  Bottom Layer w10: v1(5392,3854) 5396,3850 5426,3850 5458,3882 v1(5612,3882) ; 5762,3765 D4.1@5837,3765 ; D4.1@5840,3762 v1(5866,3736) ; J4.7@6515.8,3891.7 6515.8,3981.7
SIM_RST: R19.1 U3.12 | length 34.1
  Top Layer w10: R19.1@5177.04,3685 v1(5179.6,3685)
  Bottom Layer w10: v1(5179.6,3685) 5209.6,3685 U3.12@5209.57,3686.53
SIM_VDD: C16.1 C17.1 D6.1 J4.1 R18.2 U3.14 | length 2884.7
  Top Layer w10: 5322,3794 5323,3795 5364,3836 5366,3838 ; 5364,3852 5364,3880 ; 5366,3880 5389.5,3903.5 v1(5398,3912)
  Top Layer w15: 5354,3904 5355,3903.5
  Top Layer w16: v1(5250,3838) 5288,3838 5354,3904 ; v1(5290,3884) 5310,3904 5354,3904 ; 5318,3795 5323,3795 R18.2@5352.96,3795 ; R18.2@5350,3802 5364,3816 5364,3836 5364,3852 5354,3862 5354,3904 ; 5355,3903.5 5389.5,3903.5 C16.1@5445,3903.46 ; C16.1@5445,3898.5 C17.1@5505,3898.46
  Inner2 w10: v1(5398,3912) 5398,3924 5488,4014 5500,4014 5518,4032 v1(5518,4066)
  Bottom Layer w10: 5262,3754 5250,3766 5238,3778 5238,3880 5285,3927 5326,3968 5328,3968 5358,3998 5358,4014 ; 5314,3752 5318,3752 ; 5321.8,3732.8 5321.8,3747.8 ; v1(5518,4066) 5500,4066 ; 6365.8,3801.7 6365.8,3802 ; J4.1@6365.8,3891.7 6365.8,3802 ; 6366,3802 6365.8,3802 ; 5358,4014 5382,4038 5428,4038 5428,4044 5450,4066 ; 5358,4014 5358,4044 5380,4066 5450,4066 ; 5450,4066 5500,4066 ; 5500,4066 5562,4004 5832,4004 5910,3926 5910,3898 6006,3802 6365.8,3802
  Bottom Layer w16: v1(5250,3838) 5250,3766 5250,3752 5314,3752 ; D6.1@5285,3904 5285,3927 5285,3994 ; v1(5290,3884) D6.1@5290,3898 ; 5321.8,3747.8 U3.14@5321.77,3792.84
TP_GPIO45: U2.26
TP_GPIO46: U2.16
TP_INT: J5.12 U2.22 | length 361.4
  Top Layer w10: J5.12@4585.7,4364.1 4640,4309.8 U2.22@4640,4025.2
TP_RST: J5.11 U2.23 | length 90
  Top Layer w10: 4590,4055.2 4590,4085.2
  Top Layer w15: v1(4536.4,4334.1) J5.11@4536.4,4364.1 ; U2.23@4590,4025.2 4590,4055.2
UART0_RXD: J8.4 U2.36 | length 780.8
  Top Layer w10: U2.36@4370.51,3524.8 4460.5,3524.8 ; 4414,3528 v1(4414,3540)
  Inner2 w10: v1(4414,3540) 4412,3540 4388,3564 4388,3760 4330,3818 4328,3818 4294,3852 4294,3874 4370,3950 v1(4420,3950)
  Bottom Layer w10: v1(4420,3950) 4452,3982 ; 4451.3,3982.8 J8.4@4451.32,4072.75
UART0_TXD: J8.3 U2.37 | length 749
  Top Layer w10: U2.37@4370.51,3474.8 4460.5,3474.8 ; v1(4424,3830) v1(4424,3906) ; 4464,3478 4476,3478 v1(4476,3546)
  Bottom Layer w10: v1(4424,3830) 4424,3598 v1(4476,3546) ; v1(4424,3906) 4500,3982 ; 4500.5,3982.8 J8.3@4500.53,4072.75
USB_DM: D1.1 J2.A7 J2.B7 R9.2 | length 4666.2
  Top Layer w5: v1(3428,4058) 3428,4082 3450,4104 3558,4104 3580,4126 3580,4546 3602,4568 3680,4568
  Top Layer w10: v1(3274,4048) 3324,4098 3324,4550 3346,4572 3676,4572 3680,4568 D1.1@3701.2,4546.8 ; D1.1@3701.22,4545 D1.1@3701.2,4546.8 ; 3701.2,4635 D1.1@3701.2,4546.8 ; D1.1@3702,4546 D1.1@3701.2,4546.8 ; D1.1@3702,4558 3716,4572 3936,4572 3936,4554 3938,4552 3938,4406 3974,4406 3974,4408 3992,4426 4068,4426 4078,4436 4110,4436 4130,4456 4152,4456 4156,4460 4214,4460 4232,4478 4300,4478 v1(4340,4518) ; v1(5148,3902) v1@5152,3902 ; R9.2@5157.04,3870 v1@5157,3905
  Inner2 w10: v1(5148,3902) 5154,3908 5284,3908 5284,4016 v1(5308,4040)
  Bottom Layer w5: J2.A7@3321.79,4093.3 3381.8,4093.3 ; 3384,4094 3386,4096 3404,4096 3406,4094 3428,4094 v1(3428,4058)
  Bottom Layer w10: 3231.8,4053.9 J2.B7@3321.79,4053.93 ; v1(3274,4048) v1@3274,4050 ; v1(4340,4518) 4350,4508 4408,4508 4444,4544 4640,4544 4686,4590 4746,4590 4760,4604 4790,4604 4818,4632 5150,4632 5264,4518 5264,4418 5298,4384 5298,4050 v1(5308,4040)
USB_DM_MCU: R9.1 U2.13 | length 110
  Top Layer w10: R9.1@5122.96,3870 5122.96,3895.86 5094.02,3924.81 U2.13@5068.2,3924.81 ; U2.13@5068.2,3924.81 U2.13@5059.49,3924.8 U2.13@5068.2,3924.81
USB_DP: D2.1 J2.A6 J2.B6 R10.2 | length 3664.6
  Top Layer w10: v1(3618,4088) v1(3638,4108) 3638,4346 3702,4410 3794,4318 3834,4358 3964,4358 4016,4410 4074,4410 4084,4420 4116,4420 4136,4440 4158,4440 4162,4444 4220,4444 4238,4462 4310,4462 4334,4486 4526,4486 4584,4544 4614,4544 4634,4564 4660,4564 4686,4590 4810,4590 v1(4826,4606) ; 3701.2,4410 D2.1@3701.22,4500 ; 5162,3965 R10.2@5162.04,4025 ; 5166,3962 5226,3962 5254,3990 v1(5316,3990)
  Bottom Layer w10: 3231.8,4073.6 J2.A6@3321.79,4073.62 ; 3254,4078 3288,4112 ; 3288,4113 J2.B6@3321.79,4112.99 3450,4113 ; 3410,4108 3454,4108 ; 3450,4112 3454,4108 ; v1(3618,4088) 3474,4088 3454,4108 ; v1(3638,4108) 3454,4108 ; v1(4826,4606) 4830,4602 5154,4602 5248,4508 5248,4412 5282,4378 5282,4024 v1(5316,3990)
USB_DP_MCU: R10.1 U2.14 | length 514.1
  Top Layer w10: v1(4975.1,3850.34) 4975.1,3858.99 5018.45,3902.34 5018.45,3970.23 5023.03,3974.81 U2.14@5059.49,3974.8 ; R10.1@5127.96,4025 5133.44,4030.48 v1(5133.44,4070.41)
  Inner2 w10: v1(4975.1,3850.34) 4975.1,3876.7 5133.44,4035.04 v1(5133.44,4070.41)
VBAT: C1.1 J1.1 R28.1 U1.2 U1.3 U5.2 U5.3 | length 5702.4
  Top Layer w10: v1(5256,3306) 5352,3306 5472,3186 6510,3186 J1.1@6548,3148
  Top Layer w12: v1(3352,3780) 3358,3786 3412,3786 3418,3780 ; v1@3364,3846 3364.4,3846 v1(3376,3846) v1(3402,3846) ; C1.1@3364,3872 3364.4,3872.4 3376,3884 3402,3910 ; v1(3376,3788) v1@3382,3794 ; 3376,3858 3402,3884 3402,3910 ; 3385.9,3794.8 U1.2@3460.95,3794.84 ; v1(3402,3924) 3402,3910 ; 3415.9,3775.2 U1.3@3460.95,3775.16 ; v1(3458,3930) 3456,3928 3420,3928 3402,3910 ; U5.2@3650.16,3758.09 3654,3750 v1(3668,3736) ; 3669.8,3723.1 U5.3@3669.84,3758.09 ; 3674,3720 v1(3688,3720)
  Top Layer w15: v1@5150,3154 v1(5158,3154)
  Top Layer w16: v1@3364,3846 v1@3364.4,3846.4 ; v1@3364.4,3845 3364.4,3846 v1@3364.4,3846.4 ; C1.1@3364.37,3890 3364.4,3872.4 v1@3364.4,3846.4 ; v1(3376,3930) 3376,3884 3376,3858 v1@3364.4,3846.4 ; 5150,3098 5150,3154 R28.1@5150,3187.96
  Inner2 w10: 5198,3306 v1(5256,3306)
  Inner2 w16: v1(4852,3428) 4966,3314 4990,3314 5110,3434 5166,3434 5184,3416 5184,3356 5190,3350 5190,3186 v1(5158,3154)
  Bottom Layer w12: v1(3352,3780) 3376,3804 ; v1(3376,3788) 3376,3804 ; v1(3376,3846) 3376,3804 ; 3402,3830 3400,3828 3376,3804 ; v1(3402,3846) v1(3402,3924) ; 3408,3784 3410,3782 3426,3766 3502,3766 ; v1(3458,3930) 3480,3908 3480,3788 3486,3782 3502,3766 ; 3642,3766 3638,3766 ; v1@3686,3718 v1(3668,3736) 3638,3766 ; 3502,3766 3616,3766 3638,3766
  Bottom Layer w16: v1(3376,3930) 3400,3906 3400,3828 3400,3788 ; 3402,3790 3408,3784 ; 3406,3782 3410,3782 3486,3782 3600,3782 3616,3766 3802,3580 3802,3336 3914,3336 4010,3432 4242,3432 4250,3424 4250,3336 4328,3336 4356,3364 4356,3414 4370,3428 v1(4852,3428)
VBAT_MODEM: C32.1 C33.1 C34.1 C35.1 R28.2 U3.42 U3.43 | length 3534.7
  Top Layer w15: v1(5126,3214) R28.2@5150,3222.04
  Top Layer w16: C33.1@5305,3199.37 5380,3199.4 ; C35.1@5380,3161.54 5380,3199.4 ; 5380,3251.5 5380,3199.4 ; 5395,3199.4 5380,3199.4 ; v1@5402,3196 v1(5412,3196) ; 5450,3564.4 C34.1@5510,3564.37 ; C34.1@5504,3572 5516,3584 5822,3584 5846,3560 v1(5932,3560)
  Bottom Layer w16: v1(5126,3214) 5158,3182 5250,3182 5268,3200 ; 5268,3196 v1(5412,3196) 5722,3196 ; 5365.1,3057.2 U3.43@5365.08,3147.16 ; 5372,3072 5408.4,3072 ; v1(5388,3188) 5730,3188 ; 5408.4,3057.2 5408.4,3072 ; U3.42@5408.39,3147.16 5408.4,3072 ; 5718,3200 5722,3196 ; v1(5932,3560) C32.1@6043.4,3448.6 ; C32.1@6043.31,3448.62 C32.1@6043.4,3448.6 ; 6133.3,3448.6 C32.1@6043.4,3448.6 ; 5408.4,3072 5696,3072 5774,3150 ; 5722,3196 5730,3188 ; 5730,3188 5736,3182 5812,3182 ; 5774,3150 5890,3150 5890,3152 ; 5774,3150 5776,3152 5890,3152 ; 5812,3182 5890,3260 ; 5812,3182 5824,3182 ; 5824,3182 5890,3248 ; 5824,3182 5848,3182 5890,3224 ; 5890,3152 5890,3224 ; 5890,3224 5890,3248 ; 5890,3248 5890,3260 ; 5890,3260 5890,3294 6044,3448 C32.1@6043.4,3448.6
VBUS_PROT: C2.1 C3.1 D8.1 F1.2 U1.13 | length 1031.4
  Top Layer w6: C2.1@3610,3893.46 3598.9,3893.5 v1(3570.71,3865.31) ; v1(3570.71,3865.31) 3570.71,3844.1 U1.13@3549.53,3844.05 v1(3570.71,3865.31)
  Top Layer w10: C3.1@3475,3980.63 3475,3959.39 v1(3496.21,3959.39) ; C3.1@3475,3980.63 3621.89,4127.52 3621.89,4467.52 3631.89,4477.52 F1.2@3631.89,4524 ; C2.1@3610,3893.46 3669.1,3893.5 D8.1@3690,3872.6
  Bottom Layer w10: v1(3496.21,3959.39) 3496.21,3865.31 v1(3570.71,3865.31)
VBUS_RAW: F1.1 J2.A4B9 J2.B4A9 | length 1385.9
  Top Layer w10: v1(3558.11,4454) 3518.11,4494 F1.1@3518.11,4524 3565.77,4524
  Top Layer w16: v1(3372,3994) 3372,4084 3414,4126 ; 3412,4126 v1(3412,4188) 3412,4508 ; 3412,4510 3412,4508 ; 3428,4524 3412,4508 ; 3428.1,4524 F1.1@3518.11,4524
  Bottom Layer w10: v1(3558.11,4454) 3568.11,4444 3608.11,4444 3628.11,4464 ; 3608.15,4533.3 3618.11,4523.34 3618.11,4494 3628.11,4484 3628.11,4464 ; 3801.85,4533.3 3801.85,4507.74 3782.12,4488.02 3782.12,4448.02 3768.11,4434 3658.11,4434 3628.11,4464
  Bottom Layer w16: J2.A4B9@3321.79,3986.61 3411.8,3986.6 ; J2.B4A9@3321.79,4180.31 v1@3411.8,4180.3
VSYS_RAW: C4.1 C5.1 C19.1 U1.5 U1.10 U1.11 U4.1 U4.10 | length 4083.9
  Top Layer w10: 3660,3454.9 U4.1@3733.1,3454.9 ; v1(3716,3472) U4.1@3733.1,3454.9 ; U4.1@3734,3454 U4.1@3733.1,3454.9 ; U4.1@3735.02,3454.87 U4.1@3733.1,3454.9 ; U4.10@3799.98,3454.87 3800,3544 ; 3800,3544.9 3800,3544 ; v1(3832,3576) 3800,3544 ; v1(3938,3836) 3946,3836 v1@3948,3836
  Top Layer w12: U1.10@3579.05,3775.16 3607.1,3775.2 ; U1.10@3580,3780 U1.11@3580,3794 ; v1(3606,3732) 3610,3736 3610,3774 3608,3776 ; v1(3946,3808) 3946,3810 3946,3814 3946,3836 v1@3946,3838
  Top Layer w15: U1.5@3490,3726 3490,3702 3506,3686 v1(3520,3686) ; v1@3958,3844 v1(3962,3844)
  Top Layer w20: 3380,3676.5 C5.1@3470,3676.54 ; v1(3438,3658) 3456,3676 C5.1@3470,3676 ; C4.1@3545.63,3615 v1@3545.6,3660 ; v1(3942,3782) 3958,3798 3946,3810 3944,3812 3946,3814 3958,3826 ; 3950.6,3840 C19.1@3950.63,3930 ; v1@3955,3835 v1(3970,3820)
  Inner2 w10: v1(3716,3472) 3921,3677 3934,3690 v1(3938,3690)
  Inner2 w12: v1(3606,3732) 3642,3768 3906,3768 v1(3946,3808)
  Inner2 w15: v1(3772,3570) 3890,3688 3910,3688 3921,3677 v1(3936,3662)
  Inner2 w20: v1(3438,3658) 3628,3468 3644,3468 ; v1(3546,3654) 3546,3566 3644,3468 ; v1(3986,3664) 3946,3624 ; v1(3986,3690) 3946,3650 3946,3624 ; 3644,3468 3650,3468 3652,3466 ; 3644,3468 3646,3466 3652,3466 ; 3652,3466 3946,3466 3946,3624
  Bottom Layer w10: v1(3832,3576) 3792,3616 3792,3816 3850,3874 3936,3874 v1(3946,3864) ; v1(3938,3690) v1(3938,3836)
  Bottom Layer w15: v1(3520,3686) 3528,3694 3562,3694 3588,3668 3662,3668 3760,3570 v1(3772,3570) ; v1(3936,3662) 3954,3680 3954,3696 3954,3722 3954,3726 3950,3730 ; 3944,3736 3946,3734 ; 3944,3794 3944,3826 v1(3962,3844)
  Bottom Layer w18: 3946,3734 3950,3730
  Bottom Layer w20: 3942,3730 3942,3734 ; 3944,3736 3942,3734 ; 3946,3726 3946,3704 3954,3696 v1(3986,3664) ; v1(3970,3820) 3944,3794 3942,3792 3942,3734 ; v1(3986,3690) 3954,3722 3942,3734
pads on no net: J2.A8 J2.B8 J4.6 LED1.1 U1.9 U1.15 U2.28 U2.29 U2.30 U3.2 U3.3 U3.4 U3.5 U3.6 U3.8 U3.9 U3.16 U3.20 U3.21 U3.22 U3.23 U3.26 U3.28 U3.29 U3.30 U3.31 U3.32 U3.33 U3.38 U3.39 U3.44 U3.49 U3.50 U3.51 U3.52 U3.53 U3.54 U3.55 U3.56 U3.57 U3.58 U3.59 U3.60 U3.61 U3.62 U3.63 U3.64 U3.65 U3.66 U3.67 U3.68 U3.69 U3.74 U3.75 U3.76 U3.77 U3.78 U3.79 U3.80 U3.81 U3.82 U3.83 U3.84 U3.85 U3.86 U3.87 U3.96 U3.97 U3.98 U3.99 U3.101 U3.102 U3.103 U3.104 U3.105 U3.106 U3.107 U3.108 U3.109 U4.5 U5.5 U5.6 U6.4 U9.9

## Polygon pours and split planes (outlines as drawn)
GND on Top Layer (solid, remove dead copper, pour order 0): 3020,3020 3020,5145.4 6917,5145.4 6917,3020
GND on Bottom Layer (solid, remove dead copper, pour order 2): 3020,3020 3020,5145.4 6917,5145.4 6917,3020
GND on Inner1 (solid, remove dead copper): 3020,3020 3020,5145.4 6917,5145.4 6917,3020
+3V3 on Inner2 (solid, remove dead copper): 3020,3020 3020,5145.4 6917,5145.4 6917,3020

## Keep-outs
Board Outline Layer:
  region: 4320.98,3019.53 4320.98,3299.8 5109.02,3299.8 5109.02,3019.53
  region: 4835.36,4324.86 4835.36,4635.14 5164.64,4635.14 5164.64,4324.86
  lines w10: 3000,3080 3001.54,3064.39 3006.09,3049.39 3013.48,3035.55 3023.43,3023.43 3035.55,3013.48 3049.39,3006.09 3064.39,3001.54 3080,3000 6857,3000 6872.61,3001.54 6887.61,3006.09 6901.45,3013.48 6913.57,3023.43 6923.52,3035.55 6930.91,3049.39 6935.46,3064.39 6937,3080 6937,5085.4 6935.46,5101.01 6930.91,5116.01 6923.52,5129.85 6913.57,5141.97 6901.45,5151.92 6887.61,5159.31 6872.61,5163.86 6857,5165.4 3080,5165.4 3064.39,5163.86 3049.39,5159.31 3035.55,5151.92 3023.43,5141.97 3013.48,5129.85 3006.09,5116.01 3001.54,5101.01 3000,5085.4 3000,3080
